VERSION 5.8 ;
BUSBITCHARS "[]" ;
DIVIDERCHAR "/" ;
UNITS
    DATABASE MICRONS 2000 ;
END UNITS

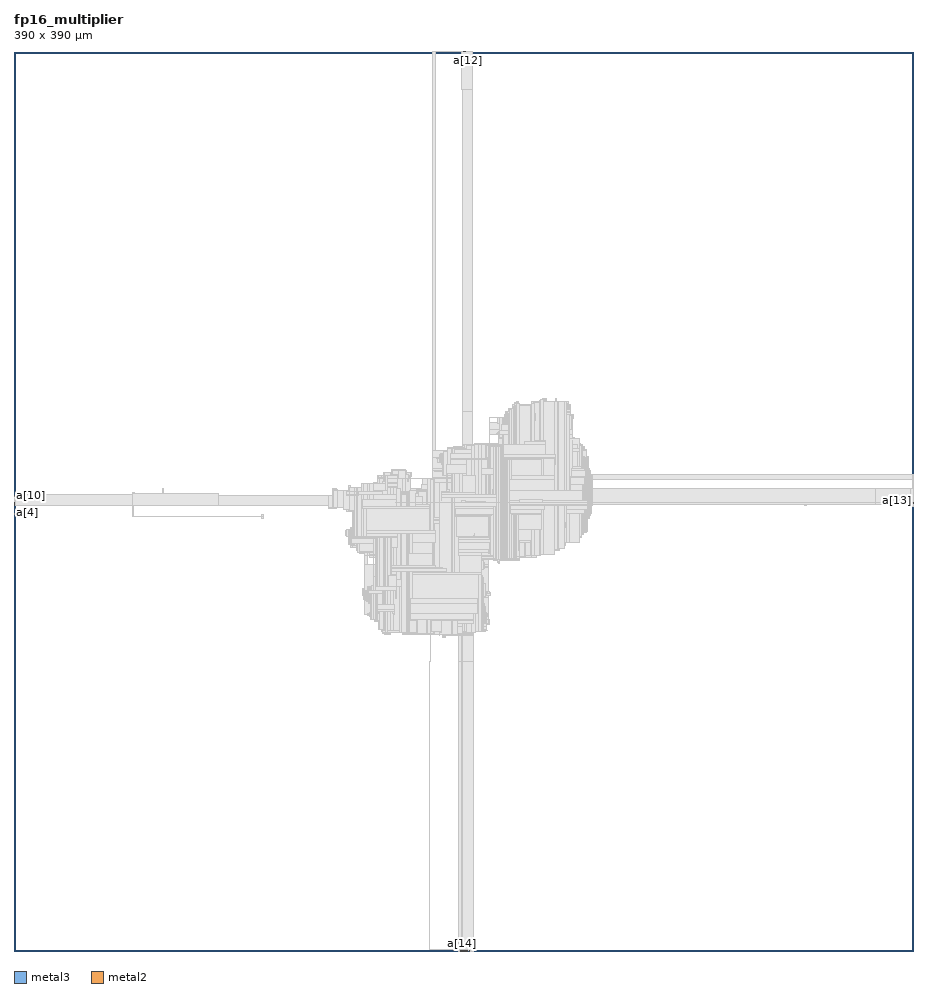
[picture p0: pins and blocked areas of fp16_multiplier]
MACRO fp16_multiplier
  FOREIGN fp16_multiplier 0 0 ;
  CLASS BLOCK ;
  SIZE 390 BY 390 ;
  PIN a[0]
    DIRECTION INPUT ;
    USE SIGNAL ;
    PORT
      LAYER metal3 ;
        RECT  0 194.915 0.07 194.985 ;
    END
  END a[0]
  PIN a[10]
    DIRECTION INPUT ;
    USE SIGNAL ;
    PORT
      LAYER metal3 ;
        RECT  0 197.155 0.07 197.225 ;
    END
  END a[10]
  PIN a[11]
    DIRECTION INPUT ;
    USE SIGNAL ;
    PORT
      LAYER metal3 ;
        RECT  0 196.035 0.07 196.105 ;
    END
  END a[11]
  PIN a[12]
    DIRECTION INPUT ;
    USE SIGNAL ;
    PORT
      LAYER metal2 ;
        RECT  196.9 389.93 196.97 390 ;
    END
  END a[12]
  PIN a[13]
    DIRECTION INPUT ;
    USE SIGNAL ;
    PORT
      LAYER metal3 ;
        RECT  389.93 195.195 390 195.265 ;
    END
  END a[13]
  PIN a[14]
    DIRECTION INPUT ;
    USE SIGNAL ;
    PORT
      LAYER metal2 ;
        RECT  194.24 0 194.31 0.07 ;
    END
  END a[14]
  PIN a[15]
    DIRECTION INPUT ;
    USE SIGNAL ;
    PORT
      LAYER metal3 ;
        RECT  0 193.795 0.07 193.865 ;
    END
  END a[15]
  PIN a[1]
    DIRECTION INPUT ;
    USE SIGNAL ;
    PORT
      LAYER metal3 ;
        RECT  389.93 196.875 390 196.945 ;
    END
  END a[1]
  PIN a[2]
    DIRECTION INPUT ;
    USE SIGNAL ;
    PORT
      LAYER metal3 ;
        RECT  389.93 197.715 390 197.785 ;
    END
  END a[2]
  PIN a[3]
    DIRECTION INPUT ;
    USE SIGNAL ;
    PORT
      LAYER metal2 ;
        RECT  196.14 0 196.21 0.07 ;
    END
  END a[3]
  PIN a[4]
    DIRECTION INPUT ;
    USE SIGNAL ;
    PORT
      LAYER metal3 ;
        RECT  0 193.235 0.07 193.305 ;
    END
  END a[4]
  PIN a[5]
    DIRECTION INPUT ;
    USE SIGNAL ;
    PORT
      LAYER metal2 ;
        RECT  195 0 195.07 0.07 ;
    END
  END a[5]
  PIN a[6]
    DIRECTION INPUT ;
    USE SIGNAL ;
    PORT
      LAYER metal2 ;
        RECT  194.62 0 194.69 0.07 ;
    END
  END a[6]
  PIN a[7]
    DIRECTION INPUT ;
    USE SIGNAL ;
    PORT
      LAYER metal3 ;
        RECT  389.93 193.515 390 193.585 ;
    END
  END a[7]
  PIN a[8]
    DIRECTION INPUT ;
    USE SIGNAL ;
    PORT
      LAYER metal2 ;
        RECT  195.76 389.93 195.83 390 ;
    END
  END a[8]
  PIN a[9]
    DIRECTION INPUT ;
    USE SIGNAL ;
    PORT
      LAYER metal2 ;
        RECT  193.86 389.93 193.93 390 ;
    END
  END a[9]
  PIN b[0]
    DIRECTION INPUT ;
    USE SIGNAL ;
    PORT
      LAYER metal2 ;
        RECT  194.62 389.93 194.69 390 ;
    END
  END b[0]
  PIN b[10]
    DIRECTION INPUT ;
    USE SIGNAL ;
    PORT
      LAYER metal2 ;
        RECT  193.86 0 193.93 0.07 ;
    END
  END b[10]
  PIN b[11]
    DIRECTION INPUT ;
    USE SIGNAL ;
    PORT
      LAYER metal3 ;
        RECT  389.93 192.675 390 192.745 ;
    END
  END b[11]
  PIN b[12]
    DIRECTION INPUT ;
    USE SIGNAL ;
    PORT
      LAYER metal3 ;
        RECT  389.93 195.475 390 195.545 ;
    END
  END b[12]
  PIN b[13]
    DIRECTION INPUT ;
    USE SIGNAL ;
    PORT
      LAYER metal2 ;
        RECT  195 389.93 195.07 390 ;
    END
  END b[13]
  PIN b[14]
    DIRECTION INPUT ;
    USE SIGNAL ;
    PORT
      LAYER metal3 ;
        RECT  389.93 196.035 390 196.105 ;
    END
  END b[14]
  PIN b[15]
    DIRECTION INPUT ;
    USE SIGNAL ;
    PORT
      LAYER metal3 ;
        RECT  389.93 194.355 390 194.425 ;
    END
  END b[15]
  PIN b[1]
    DIRECTION INPUT ;
    USE SIGNAL ;
    PORT
      LAYER metal3 ;
        RECT  0 194.355 0.07 194.425 ;
    END
  END b[1]
  PIN b[2]
    DIRECTION INPUT ;
    USE SIGNAL ;
    PORT
      LAYER metal2 ;
        RECT  195.38 389.93 195.45 390 ;
    END
  END b[2]
  PIN b[3]
    DIRECTION INPUT ;
    USE SIGNAL ;
    PORT
      LAYER metal2 ;
        RECT  195.38 0 195.45 0.07 ;
    END
  END b[3]
  PIN b[4]
    DIRECTION INPUT ;
    USE SIGNAL ;
    PORT
      LAYER metal3 ;
        RECT  0 194.075 0.07 194.145 ;
    END
  END b[4]
  PIN b[5]
    DIRECTION INPUT ;
    USE SIGNAL ;
    PORT
      LAYER metal2 ;
        RECT  196.52 389.93 196.59 390 ;
    END
  END b[5]
  PIN b[6]
    DIRECTION INPUT ;
    USE SIGNAL ;
    PORT
      LAYER metal3 ;
        RECT  389.93 195.755 390 195.825 ;
    END
  END b[6]
  PIN b[7]
    DIRECTION INPUT ;
    USE SIGNAL ;
    PORT
      LAYER metal2 ;
        RECT  197.28 0 197.35 0.07 ;
    END
  END b[7]
  PIN b[8]
    DIRECTION INPUT ;
    USE SIGNAL ;
    PORT
      LAYER metal3 ;
        RECT  0 196.595 0.07 196.665 ;
    END
  END b[8]
  PIN b[9]
    DIRECTION INPUT ;
    USE SIGNAL ;
    PORT
      LAYER metal3 ;
        RECT  389.93 196.595 390 196.665 ;
    END
  END b[9]
  PIN result[0]
    DIRECTION OUTPUT ;
    USE SIGNAL ;
    PORT
      LAYER metal2 ;
        RECT  194.24 389.93 194.31 390 ;
    END
  END result[0]
  PIN result[10]
    DIRECTION OUTPUT ;
    USE SIGNAL ;
    PORT
      LAYER metal3 ;
        RECT  389.93 194.075 390 194.145 ;
    END
  END result[10]
  PIN result[11]
    DIRECTION OUTPUT ;
    USE SIGNAL ;
    PORT
      LAYER metal3 ;
        RECT  0 193.515 0.07 193.585 ;
    END
  END result[11]
  PIN result[12]
    DIRECTION OUTPUT ;
    USE SIGNAL ;
    PORT
      LAYER metal3 ;
        RECT  389.93 193.795 390 193.865 ;
    END
  END result[12]
  PIN result[13]
    DIRECTION OUTPUT ;
    USE SIGNAL ;
    PORT
      LAYER metal2 ;
        RECT  193.48 0 193.55 0.07 ;
    END
  END result[13]
  PIN result[14]
    DIRECTION OUTPUT ;
    USE SIGNAL ;
    PORT
      LAYER metal2 ;
        RECT  195.76 0 195.83 0.07 ;
    END
  END result[14]
  PIN result[15]
    DIRECTION OUTPUT ;
    USE SIGNAL ;
    PORT
      LAYER metal3 ;
        RECT  0 194.635 0.07 194.705 ;
    END
  END result[15]
  PIN result[1]
    DIRECTION OUTPUT ;
    USE SIGNAL ;
    PORT
      LAYER metal3 ;
        RECT  0 195.195 0.07 195.265 ;
    END
  END result[1]
  PIN result[2]
    DIRECTION OUTPUT ;
    USE SIGNAL ;
    PORT
      LAYER metal3 ;
        RECT  389.93 196.315 390 196.385 ;
    END
  END result[2]
  PIN result[3]
    DIRECTION OUTPUT ;
    USE SIGNAL ;
    PORT
      LAYER metal3 ;
        RECT  389.93 194.915 390 194.985 ;
    END
  END result[3]
  PIN result[4]
    DIRECTION OUTPUT ;
    USE SIGNAL ;
    PORT
      LAYER metal3 ;
        RECT  0 195.755 0.07 195.825 ;
    END
  END result[4]
  PIN result[5]
    DIRECTION OUTPUT ;
    USE SIGNAL ;
    PORT
      LAYER metal3 ;
        RECT  0 195.475 0.07 195.545 ;
    END
  END result[5]
  PIN result[6]
    DIRECTION OUTPUT ;
    USE SIGNAL ;
    PORT
      LAYER metal2 ;
        RECT  196.52 0 196.59 0.07 ;
    END
  END result[6]
  PIN result[7]
    DIRECTION OUTPUT ;
    USE SIGNAL ;
    PORT
      LAYER metal3 ;
        RECT  0 196.315 0.07 196.385 ;
    END
  END result[7]
  PIN result[8]
    DIRECTION OUTPUT ;
    USE SIGNAL ;
    PORT
      LAYER metal2 ;
        RECT  193.48 389.93 193.55 390 ;
    END
  END result[8]
  PIN result[9]
    DIRECTION OUTPUT ;
    USE SIGNAL ;
    PORT
      LAYER metal3 ;
        RECT  389.93 194.635 390 194.705 ;
    END
  END result[9]
  OBS
    LAYER metal1 ;
     RECT  51.49 195.915 52.25 198.885 ;
     RECT  57 193.115 57.57 194.685 ;
     RECT  57.57 193.115 57.76 196.085 ;
     RECT  57.76 194.515 58.33 196.085 ;
     RECT  64.22 198.715 64.79 200.285 ;
     RECT  87.97 195.915 88.54 197.485 ;
     RECT  92.15 194.515 92.72 196.085 ;
     RECT  107.35 187.515 107.92 189.085 ;
     RECT  136.04 195.915 136.23 197.485 ;
     RECT  136.23 191.715 137.94 197.485 ;
     RECT  137.94 191.715 139.65 200.285 ;
     RECT  139.65 193.115 139.84 200.285 ;
     RECT  139.84 193.115 140.6 198.885 ;
     RECT  140.6 193.115 143.45 197.485 ;
     RECT  143.45 193.115 144.02 198.885 ;
     RECT  143.83 180.515 144.78 182.085 ;
     RECT  144.02 190.315 144.97 198.885 ;
     RECT  144.78 176.315 145.73 182.085 ;
     RECT  144.97 190.315 145.73 201.685 ;
     RECT  145.73 174.915 146.87 183.485 ;
     RECT  145.73 190.315 146.87 198.885 ;
     RECT  146.87 174.915 148.58 198.885 ;
     RECT  148.58 173.515 149.53 198.885 ;
     RECT  149.53 172.115 151.24 198.885 ;
     RECT  151.05 155.315 151.43 156.885 ;
     RECT  151.43 152.515 152.19 156.885 ;
     RECT  152.19 148.315 152.57 156.885 ;
     RECT  151.24 172.115 152.57 200.285 ;
     RECT  152.57 146.915 152.76 156.885 ;
     RECT  152.76 146.915 153.14 158.285 ;
     RECT  152.57 172.115 154.09 201.685 ;
     RECT  153.14 145.515 154.47 158.285 ;
     RECT  154.47 144.115 155.8 158.285 ;
     RECT  154.09 170.715 155.8 201.685 ;
     RECT  155.8 144.115 156.37 162.485 ;
     RECT  156.37 142.715 156.56 162.485 ;
     RECT  155.8 170.715 156.56 203.085 ;
     RECT  156.56 142.715 157.32 203.085 ;
     RECT  157.32 142.715 157.89 205.885 ;
     RECT  157.89 139.915 159.22 205.885 ;
     RECT  159.22 138.515 160.17 205.885 ;
     RECT  160.17 138.515 160.55 207.285 ;
     RECT  160.55 137.115 163.21 207.285 ;
     RECT  163.21 138.515 163.4 207.285 ;
     RECT  163.4 138.515 168.34 208.685 ;
     RECT  168.34 137.115 169.86 208.685 ;
     RECT  169.86 137.115 171.76 207.285 ;
     RECT  171.76 205.715 172.33 207.285 ;
     RECT  171.76 137.115 176.89 200.285 ;
     RECT  176.89 137.115 180.12 203.085 ;
     RECT  180.12 137.115 181.64 204.485 ;
     RECT  181.64 137.115 182.97 208.685 ;
     RECT  182.97 137.115 184.49 212.885 ;
     RECT  184.49 137.115 185.63 215.685 ;
     RECT  185.63 137.115 185.82 217.085 ;
     RECT  185.82 135.715 187.15 217.085 ;
     RECT  187.15 137.115 190.38 217.085 ;
     RECT  190.38 137.115 192.09 218.485 ;
     RECT  192.09 138.515 197.22 218.485 ;
     RECT  197.22 137.115 198.93 218.485 ;
     RECT  198.93 138.515 199.5 218.485 ;
     RECT  199.5 138.515 203.49 219.885 ;
     RECT  203.49 141.315 203.87 219.885 ;
     RECT  203.87 165.115 204.06 168.085 ;
     RECT  203.87 141.315 204.44 159.685 ;
     RECT  204.44 141.315 204.63 158.285 ;
     RECT  204.63 153.915 204.82 158.285 ;
     RECT  204.63 141.315 205.2 147.085 ;
     RECT  205.2 141.315 205.77 144.285 ;
     RECT  205.77 141.315 205.96 142.885 ;
     RECT  204.82 153.915 206.34 155.485 ;
     RECT  203.87 172.115 206.91 219.885 ;
     RECT  206.91 170.715 207.86 219.885 ;
     RECT  209.19 223.915 209.38 225.485 ;
     RECT  207.86 169.315 209.95 219.885 ;
     RECT  209.95 167.915 210.33 219.885 ;
     RECT  209.38 223.915 210.33 229.685 ;
     RECT  210.33 167.915 210.52 229.685 ;
     RECT  210.52 169.315 210.9 229.685 ;
     RECT  210.9 169.315 212.61 231.085 ;
     RECT  212.61 169.315 212.99 232.485 ;
     RECT  212.99 169.315 214.32 233.885 ;
     RECT  214.32 169.315 216.03 235.285 ;
     RECT  216.03 169.315 217.74 236.685 ;
     RECT  217.74 169.315 218.5 238.085 ;
     RECT  218.5 169.315 219.26 236.685 ;
     RECT  219.26 170.715 224.2 236.685 ;
     RECT  224.2 170.715 226.48 238.085 ;
     RECT  226.48 172.115 228.95 238.085 ;
     RECT  228.95 172.115 230.66 239.485 ;
     RECT  230.66 172.115 231.42 238.085 ;
     RECT  231.42 173.515 234.46 238.085 ;
     RECT  234.46 173.515 235.03 239.485 ;
     RECT  235.03 173.515 236.36 238.085 ;
     RECT  236.36 174.915 238.64 238.085 ;
     RECT  238.64 177.715 240.35 238.085 ;
     RECT  240.35 177.715 240.54 236.685 ;
     RECT  240.54 179.115 240.73 236.685 ;
     RECT  240.73 228.115 241.11 236.685 ;
     RECT  241.11 228.115 241.68 232.485 ;
     RECT  241.68 230.915 242.25 232.485 ;
     RECT  240.73 179.115 243.01 222.685 ;
     RECT  243.01 179.115 244.53 221.285 ;
     RECT  244.53 177.715 244.72 221.285 ;
     RECT  244.72 177.715 245.1 219.885 ;
     RECT  245.1 179.115 245.48 219.885 ;
     RECT  245.48 179.115 246.05 218.485 ;
     RECT  246.05 180.515 246.81 218.485 ;
     RECT  246.81 181.915 247.19 218.485 ;
     RECT  247.19 181.915 247.57 215.685 ;
     RECT  247.57 181.915 248.33 208.685 ;
     RECT  248.33 187.515 248.9 208.685 ;
     RECT  247.57 212.715 249.09 214.285 ;
     RECT  248.9 187.515 249.28 205.885 ;
     RECT  249.28 187.515 249.47 189.085 ;
     RECT  249.28 193.115 249.66 203.085 ;
     RECT  249.66 193.115 250.61 194.685 ;
     RECT  249.66 198.715 250.99 200.285 ;
     RECT  342.76 193.115 343.52 194.685 ;
    LAYER metal2 ;
     RECT  192.53 0 193.36 0.035 ;
     RECT  197.47 0 199.25 0.035 ;
     RECT  179.99 0.56 180.06 125.365 ;
     RECT  179.99 125.365 180.44 125.435 ;
     RECT  192.53 0.035 199.25 125.435 ;
     RECT  185.88 136.36 186.9 136.395 ;
     RECT  185.5 136.395 186.9 136.92 ;
     RECT  192.53 125.435 199.06 136.92 ;
     RECT  180.37 125.435 180.44 137.06 ;
     RECT  185.5 136.92 199.06 137.06 ;
     RECT  170.87 137.515 171.7 137.62 ;
     RECT  180.37 137.06 199.06 137.62 ;
     RECT  160.8 137.62 160.87 137.655 ;
     RECT  169.92 137.62 171.7 137.655 ;
     RECT  168.4 137.655 171.7 137.76 ;
     RECT  178.66 137.62 199.06 137.76 ;
     RECT  159.66 137.655 162.96 137.9 ;
     RECT  168.4 137.76 199.06 137.9 ;
     RECT  159.66 137.9 163.15 137.935 ;
     RECT  159.66 137.935 163.53 138.04 ;
     RECT  167.83 137.9 199.82 138.04 ;
     RECT  204.12 138.46 204.19 138.88 ;
     RECT  159.66 138.04 199.82 139.02 ;
     RECT  204.12 138.88 204.95 139.02 ;
     RECT  159.66 139.02 204.95 139.44 ;
     RECT  158.14 139.44 204.95 140.7 ;
     RECT  157.95 140.7 204.95 141.96 ;
     RECT  157.95 141.96 205.9 143.08 ;
     RECT  157.57 143.08 205.9 143.22 ;
     RECT  156.62 143.22 205.9 143.5 ;
     RECT  154.53 143.5 205.9 143.605 ;
     RECT  154.53 143.605 205.71 144.9 ;
     RECT  153.96 144.9 205.71 145.32 ;
     RECT  153.58 145.32 205.71 145.88 ;
     RECT  152.06 145.88 205.71 153.02 ;
     RECT  151.87 153.02 205.71 153.16 ;
     RECT  151.49 153.16 205.71 153.86 ;
     RECT  151.11 153.86 205.71 154.175 ;
     RECT  151.11 154.175 206.28 154.84 ;
     RECT  151.11 154.84 205.9 155.68 ;
     RECT  151.11 155.68 205.52 155.96 ;
     RECT  151.68 155.96 205.52 167.3 ;
     RECT  210.2 168.42 210.27 168.455 ;
     RECT  209.63 168.455 210.27 168.7 ;
     RECT  157 167.3 205.52 169.68 ;
     RECT  209.63 168.7 210.46 169.68 ;
     RECT  157 169.68 210.46 169.715 ;
     RECT  217.99 169.68 218.82 169.715 ;
     RECT  157 169.715 218.82 169.96 ;
     RECT  157 169.96 219.2 170.94 ;
     RECT  157 170.94 221.1 171.08 ;
     RECT  157 171.08 221.48 171.22 ;
     RECT  151.68 167.3 153.08 171.5 ;
     RECT  157 171.22 223.95 171.5 ;
     RECT  151.68 171.5 227.94 172.62 ;
     RECT  149.02 172.62 227.94 172.76 ;
     RECT  233.95 171.78 234.02 172.76 ;
     RECT  149.02 172.76 234.02 173.88 ;
     RECT  149.02 173.88 235.54 173.915 ;
     RECT  149.02 173.915 236.3 174.02 ;
     RECT  148.83 174.02 236.3 174.055 ;
     RECT  148.45 174.055 236.3 174.335 ;
     RECT  148.45 174.335 236.49 174.44 ;
     RECT  148.45 174.44 238.58 175.56 ;
     RECT  145.79 175.56 238.58 175.595 ;
     RECT  145.79 175.595 238.77 176.12 ;
     RECT  145.41 176.12 238.77 176.68 ;
     RECT  145.03 176.68 238.77 176.96 ;
     RECT  144.84 176.96 238.77 178.115 ;
     RECT  144.84 178.115 239.34 178.36 ;
     RECT  244.97 176.82 245.04 178.36 ;
     RECT  144.84 178.36 240.29 178.92 ;
     RECT  144.84 178.92 240.48 178.955 ;
     RECT  244.59 178.36 245.04 178.955 ;
     RECT  144.84 178.955 245.04 179.48 ;
     RECT  144.84 179.48 245.99 179.62 ;
     RECT  144.27 179.62 245.99 179.9 ;
     RECT  143.89 179.9 245.99 180.74 ;
     RECT  143.89 180.74 246.37 181.16 ;
     RECT  143.89 181.16 246.56 181.3 ;
     RECT  144.08 181.3 248.08 182.42 ;
     RECT  144.08 182.42 248.27 182.56 ;
     RECT  145.79 182.56 248.08 182.98 ;
     RECT  146.17 182.98 248.08 183.12 ;
     RECT  146.74 183.12 248.08 183.26 ;
     RECT  146.93 183.26 248.08 186.62 ;
     RECT  146.93 186.62 248.65 186.9 ;
     RECT  147.31 186.9 248.65 188.16 ;
     RECT  107.79 188.16 107.86 188.3 ;
     RECT  147.31 188.16 248.84 188.3 ;
     RECT  147.31 188.3 249.41 188.86 ;
     RECT  147.31 188.86 249.6 189.56 ;
     RECT  147.31 189.56 250.36 190.82 ;
     RECT  145.22 190.82 250.36 191.1 ;
     RECT  144.84 191.1 250.36 191.24 ;
     RECT  142.75 191.24 250.36 192.08 ;
     RECT  139.14 192.08 250.36 192.115 ;
     RECT  138.76 192.115 250.36 192.22 ;
     RECT  136.48 192.22 250.36 192.36 ;
     RECT  136.67 192.36 250.36 192.92 ;
     RECT  0.06 192.92 0.13 193.76 ;
     RECT  388.61 192.64 388.68 193.76 ;
     RECT  137.05 192.92 250.36 193.9 ;
     RECT  0.06 193.76 0.51 194.04 ;
     RECT  57.06 193.9 57.13 194.04 ;
     RECT  388.61 193.76 389.06 194.18 ;
     RECT  343.2 194.32 343.27 194.46 ;
     RECT  137.05 193.9 250.55 194.6 ;
     RECT  388.42 194.18 389.06 194.74 ;
     RECT  57.44 194.32 57.51 195.02 ;
     RECT  92.59 195.02 92.66 195.16 ;
     RECT  388.61 194.74 389.06 195.3 ;
     RECT  57.44 195.02 57.7 195.44 ;
     RECT  57.44 195.44 58.08 195.72 ;
     RECT  388.61 195.3 389.25 195.72 ;
     RECT  57.44 195.72 57.51 196.42 ;
     RECT  0.06 194.04 0.89 196.56 ;
     RECT  51.55 188.16 51.62 196.7 ;
     RECT  64.66 193.9 64.73 196.7 ;
     RECT  0.06 196.56 0.7 196.84 ;
     RECT  51.55 196.7 52.19 196.84 ;
     RECT  137.05 194.6 250.17 196.84 ;
     RECT  388.61 195.72 389.82 197.26 ;
     RECT  0.63 196.84 0.7 197.68 ;
     RECT  51.55 196.84 52 197.68 ;
     RECT  51.55 197.68 51.62 198.1 ;
     RECT  88.41 197.12 88.48 198.1 ;
     RECT  137.81 196.84 250.17 198.1 ;
     RECT  144.65 198.1 250.17 198.38 ;
     RECT  145.22 198.38 250.17 198.485 ;
     RECT  64.28 196.7 64.73 199.08 ;
     RECT  137.81 198.1 140.16 199.185 ;
     RECT  145.41 198.485 250.17 199.22 ;
     RECT  171.63 199.22 250.17 199.5 ;
     RECT  64.28 199.08 64.35 199.64 ;
     RECT  138.19 199.185 140.16 199.64 ;
     RECT  171.63 199.5 250.93 199.64 ;
     RECT  138.38 199.64 140.16 199.78 ;
     RECT  174.48 199.64 250.55 200.06 ;
     RECT  389.37 197.26 389.82 200.34 ;
     RECT  145.41 199.22 167.52 200.48 ;
     RECT  145.41 200.48 166.38 200.9 ;
     RECT  150.73 200.9 166.38 201.46 ;
     RECT  176.76 200.06 250.55 202.265 ;
     RECT  176.95 202.265 250.55 202.3 ;
     RECT  176.95 202.3 250.17 202.44 ;
     RECT  150.73 201.46 150.8 202.58 ;
     RECT  155.86 201.46 166.38 202.72 ;
     RECT  156.62 202.72 166.38 202.86 ;
     RECT  180.18 202.44 250.17 202.965 ;
     RECT  157.57 202.86 166.38 203 ;
     RECT  170.3 203.56 170.37 203.595 ;
     RECT  389.37 200.34 389.63 204.54 ;
     RECT  157.76 203 166.38 204.82 ;
     RECT  170.3 203.595 170.75 204.82 ;
     RECT  180.56 202.965 250.17 204.82 ;
     RECT  157.76 204.82 170.75 204.855 ;
     RECT  157.76 204.855 171.51 205.1 ;
     RECT  157.76 205.1 171.7 205.24 ;
     RECT  160.23 205.24 171.7 205.38 ;
     RECT  181.51 204.82 250.17 205.38 ;
     RECT  161.18 205.38 171.7 205.52 ;
     RECT  161.18 205.52 171.51 206.08 ;
     RECT  161.18 206.08 171.13 206.22 ;
     RECT  164.22 206.22 171.13 206.64 ;
     RECT  389.56 204.54 389.63 206.64 ;
     RECT  164.22 206.64 170.18 208.005 ;
     RECT  164.22 208.005 169.8 208.04 ;
     RECT  181.51 205.38 249.79 208.04 ;
     RECT  164.22 208.04 165.24 208.285 ;
     RECT  164.22 208.285 164.29 208.32 ;
     RECT  181.51 208.04 249.41 209.16 ;
     RECT  181.51 209.16 249.03 213.64 ;
     RECT  181.51 213.64 248.27 213.885 ;
     RECT  181.51 213.885 247.89 216.685 ;
     RECT  187.78 216.685 247.89 217.245 ;
     RECT  187.78 217.245 247.13 217.98 ;
     RECT  194.24 217.98 246.56 219.24 ;
     RECT  194.24 219.24 199.82 219.38 ;
     RECT  204.12 219.24 246.56 219.38 ;
     RECT  206.02 219.38 246.56 219.485 ;
     RECT  206.02 219.485 245.42 219.52 ;
     RECT  210.01 219.52 244.85 222.04 ;
     RECT  206.02 219.52 206.09 223.86 ;
     RECT  210.01 222.04 242.19 223.86 ;
     RECT  206.02 223.86 242.19 225.96 ;
     RECT  206.02 225.96 242 228.9 ;
     RECT  210.58 228.9 242 230.44 ;
     RECT  211.15 230.44 242 230.685 ;
     RECT  206.02 228.9 206.09 231.14 ;
     RECT  212.48 230.685 242 231.28 ;
     RECT  212.67 231.28 242 231.7 ;
     RECT  212.86 231.7 242 231.98 ;
     RECT  212.86 231.98 242.19 232.12 ;
     RECT  212.86 232.12 241.24 233.205 ;
     RECT  213.05 233.205 241.24 233.24 ;
     RECT  213.62 233.24 241.24 233.38 ;
     RECT  213.81 233.38 241.24 233.66 ;
     RECT  194.24 219.38 198.68 233.735 ;
     RECT  214.38 233.66 241.24 234.5 ;
     RECT  214.57 234.5 241.24 234.78 ;
     RECT  215.71 234.78 241.24 235.06 ;
     RECT  216.09 235.06 241.24 236.04 ;
     RECT  217.04 236.04 241.24 236.285 ;
     RECT  217.04 236.285 219.77 236.46 ;
     RECT  224.07 236.285 241.24 236.845 ;
     RECT  224.07 236.845 240.29 236.88 ;
     RECT  224.07 236.88 240.1 237.265 ;
     RECT  217.04 236.46 219.01 237.3 ;
     RECT  224.26 237.265 240.1 237.3 ;
     RECT  217.04 237.3 218.06 237.545 ;
     RECT  225.21 237.3 239.53 237.545 ;
     RECT  217.99 237.545 218.06 237.58 ;
     RECT  225.21 237.545 239.34 237.72 ;
     RECT  227.68 237.72 239.34 238.245 ;
     RECT  234.52 238.245 239.34 238.28 ;
     RECT  227.68 238.245 230.6 238.7 ;
     RECT  228.06 238.7 230.6 238.84 ;
     RECT  229.77 238.84 230.41 239.085 ;
     RECT  234.52 238.28 235.16 239.085 ;
     RECT  194.24 233.735 198.49 373.315 ;
     RECT  181.51 216.685 182.53 389.76 ;
     RECT  193.86 373.315 198.49 389.76 ;
     RECT  181.51 389.76 181.58 389.9 ;
     RECT  193.48 389.76 198.49 389.965 ;
     RECT  195.95 389.965 198.49 390 ;
    LAYER metal3 ;
     RECT  0.025 192.955 0.035 196.805 ;
     RECT  0.035 192.955 0.595 197.225 ;
     RECT  0.595 192.955 51.515 197.645 ;
     RECT  51.515 192.955 88.515 198.065 ;
     RECT  51.515 188.195 107.895 188.265 ;
     RECT  88.515 192.955 136.445 197.225 ;
     RECT  136.445 192.255 138.155 197.225 ;
     RECT  138.155 192.255 138.345 199.465 ;
     RECT  138.345 192.255 140.195 199.745 ;
     RECT  140.195 192.255 142.715 199.605 ;
     RECT  143.855 179.935 144.045 180.005 ;
     RECT  144.045 179.935 144.235 182.525 ;
     RECT  144.235 179.655 144.805 182.525 ;
     RECT  144.805 176.995 144.995 182.525 ;
     RECT  142.715 191.275 145.185 199.605 ;
     RECT  144.995 176.715 145.375 182.525 ;
     RECT  145.185 190.855 145.375 199.605 ;
     RECT  145.375 176.155 145.755 182.525 ;
     RECT  145.755 175.875 146.135 182.945 ;
     RECT  146.135 175.875 146.705 183.085 ;
     RECT  146.705 175.595 146.895 183.225 ;
     RECT  146.895 175.595 147.085 184.905 ;
     RECT  147.085 175.595 147.275 186.025 ;
     RECT  147.275 175.595 147.655 187.145 ;
     RECT  145.375 190.855 147.655 200.865 ;
     RECT  147.655 175.595 148.605 200.865 ;
     RECT  148.605 174.615 148.985 200.865 ;
     RECT  148.985 172.655 150.695 200.865 ;
     RECT  151.075 153.895 151.455 155.925 ;
     RECT  150.695 172.655 151.645 202.545 ;
     RECT  151.455 153.195 151.835 155.925 ;
     RECT  151.835 153.055 152.215 156.065 ;
     RECT  152.215 152.075 152.595 156.065 ;
     RECT  152.595 151.655 152.66 156.065 ;
     RECT  151.645 172.515 152.975 202.545 ;
     RECT  152.025 145.915 153.165 145.985 ;
     RECT  152.66 151.515 153.165 156.065 ;
     RECT  153.165 145.915 153.545 146.125 ;
     RECT  153.165 151.515 153.545 157.745 ;
     RECT  153.545 145.355 153.735 146.125 ;
     RECT  153.735 145.355 153.925 146.405 ;
     RECT  153.545 150.395 153.925 157.745 ;
     RECT  153.925 144.935 154.115 146.405 ;
     RECT  152.975 171.535 154.255 202.545 ;
     RECT  154.115 144.935 154.305 146.545 ;
     RECT  154.305 144.935 154.495 146.685 ;
     RECT  153.925 150.395 154.495 158.025 ;
     RECT  154.495 143.535 154.875 158.025 ;
     RECT  154.875 143.535 155.825 158.305 ;
     RECT  155.705 162.155 155.825 162.225 ;
     RECT  154.255 171.675 155.825 202.545 ;
     RECT  155.825 143.535 156.585 162.225 ;
     RECT  155.825 171.675 156.585 202.685 ;
     RECT  156.585 143.255 156.965 167.265 ;
     RECT  156.965 143.255 157.155 167.685 ;
     RECT  156.585 171.675 157.155 202.825 ;
     RECT  157.155 143.255 157.535 202.825 ;
     RECT  157.535 143.255 157.725 202.965 ;
     RECT  158.105 139.475 158.295 139.545 ;
     RECT  157.725 143.255 158.295 204.785 ;
     RECT  158.295 139.475 160.195 204.785 ;
     RECT  160.195 139.475 160.385 205.345 ;
     RECT  160.385 139.195 160.575 205.345 ;
     RECT  160.575 138.775 160.955 205.345 ;
     RECT  160.955 138.215 161.145 205.345 ;
     RECT  161.145 138.215 161.855 206.185 ;
     RECT  161.855 138.215 162.045 200.865 ;
     RECT  162.045 138.775 163.185 200.865 ;
     RECT  163.185 139.055 164.515 200.865 ;
     RECT  164.515 161.035 165.845 200.865 ;
     RECT  161.855 204.715 166.085 206.185 ;
     RECT  166.085 204.715 166.655 206.325 ;
     RECT  164.515 139.055 167.225 158.025 ;
     RECT  165.845 161.035 167.555 200.445 ;
     RECT  167.225 138.075 167.795 158.025 ;
     RECT  167.555 161.035 167.795 197.645 ;
     RECT  166.655 204.715 169.835 208.005 ;
     RECT  167.795 137.935 170.075 197.645 ;
     RECT  170.075 137.795 170.645 197.645 ;
     RECT  170.645 137.795 171.165 199.185 ;
     RECT  169.835 204.715 171.165 206.605 ;
     RECT  171.165 137.935 171.355 199.185 ;
     RECT  171.165 204.715 171.355 206.045 ;
     RECT  171.355 138.215 171.595 199.185 ;
     RECT  171.355 204.715 171.735 205.485 ;
     RECT  171.595 138.215 174.395 199.605 ;
     RECT  174.395 138.215 174.445 199.185 ;
     RECT  174.445 137.935 174.825 199.185 ;
     RECT  171.735 204.715 176.915 204.785 ;
     RECT  174.825 137.795 178.625 199.185 ;
     RECT  178.625 137.655 179.195 199.185 ;
     RECT  176.915 202.195 179.195 204.785 ;
     RECT  179.195 137.655 180.665 204.785 ;
     RECT  180.665 137.655 181.615 204.225 ;
     RECT  181.615 137.655 182.045 185.045 ;
     RECT  181.615 187.915 182.185 204.225 ;
     RECT  181.475 389.795 182.425 389.865 ;
     RECT  182.995 213.535 183.375 213.605 ;
     RECT  183.375 211.715 183.565 213.605 ;
     RECT  182.045 137.095 184.265 185.045 ;
     RECT  184.265 136.955 184.515 185.045 ;
     RECT  182.185 187.915 184.515 202.965 ;
     RECT  183.565 211.575 184.515 213.605 ;
     RECT  184.515 211.575 184.705 215.145 ;
     RECT  184.705 211.575 185.085 215.425 ;
     RECT  185.085 211.015 185.275 215.425 ;
     RECT  182.235 207.935 185.655 208.005 ;
     RECT  185.655 205.975 185.845 208.005 ;
     RECT  185.275 211.015 185.845 215.705 ;
     RECT  185.845 205.975 186.225 215.705 ;
     RECT  186.225 205.975 187.745 216.405 ;
     RECT  184.515 136.955 189.455 202.965 ;
     RECT  187.745 205.975 189.455 217.945 ;
     RECT  189.455 136.955 189.975 217.945 ;
     RECT  189.975 158.235 190.735 217.945 ;
     RECT  189.975 136.955 192.065 155.085 ;
     RECT  192.065 137.655 192.635 155.085 ;
     RECT  192.635 138.495 192.875 155.085 ;
     RECT  190.735 158.235 192.875 217.665 ;
     RECT  179.955 0.595 193.255 0.665 ;
     RECT  193.255 0.455 193.825 0.665 ;
     RECT  193.825 0.175 194.205 0.665 ;
     RECT  182.425 389.655 194.345 389.865 ;
     RECT  192.875 138.495 195.155 217.665 ;
     RECT  194.205 0.175 195.865 0.805 ;
     RECT  195.155 138.495 196.105 219.345 ;
     RECT  196.105 138.215 196.165 219.345 ;
     RECT  196.165 138.215 196.295 219.205 ;
     RECT  195.865 0.175 196.625 0.665 ;
     RECT  194.345 389.795 196.625 389.865 ;
     RECT  196.625 0.175 197.765 0.245 ;
     RECT  196.295 137.935 198.335 219.205 ;
     RECT  198.335 176.715 199.715 219.205 ;
     RECT  198.335 137.935 199.855 173.145 ;
     RECT  199.855 138.495 201.235 173.145 ;
     RECT  199.715 176.715 201.235 219.345 ;
     RECT  201.235 138.495 202.705 219.345 ;
     RECT  202.705 138.495 202.895 162.505 ;
     RECT  202.895 138.495 203.275 161.665 ;
     RECT  203.275 138.495 203.465 139.125 ;
     RECT  203.275 141.995 203.465 161.665 ;
     RECT  202.705 165.515 203.655 169.085 ;
     RECT  203.465 141.995 203.845 150.745 ;
     RECT  203.655 165.795 203.845 168.385 ;
     RECT  203.845 141.995 204.035 150.465 ;
     RECT  203.845 165.795 204.035 167.545 ;
     RECT  203.465 138.495 204.225 138.985 ;
     RECT  204.035 141.995 204.225 149.205 ;
     RECT  203.465 153.615 204.225 159.425 ;
     RECT  202.705 172.515 204.225 219.345 ;
     RECT  204.225 153.755 204.415 157.605 ;
     RECT  204.225 172.515 204.605 219.065 ;
     RECT  204.225 141.995 204.795 146.545 ;
     RECT  204.415 154.175 204.795 155.645 ;
     RECT  204.225 138.915 204.985 138.985 ;
     RECT  204.795 146.335 205.175 146.405 ;
     RECT  204.795 154.875 205.365 155.645 ;
     RECT  204.035 166.355 205.365 166.425 ;
     RECT  204.795 141.995 205.555 143.465 ;
     RECT  204.605 172.515 205.58 218.925 ;
     RECT  205.555 142.555 205.935 142.625 ;
     RECT  205.365 155.575 205.935 155.645 ;
     RECT  205.58 172.375 205.935 218.925 ;
     RECT  205.935 172.375 206.365 218.645 ;
     RECT  206.365 171.535 207.695 218.645 ;
     RECT  207.695 170.975 207.885 218.645 ;
     RECT  207.885 170.275 208.455 218.645 ;
     RECT  208.455 169.995 208.835 218.645 ;
     RECT  208.835 169.855 209.025 218.645 ;
     RECT  205.985 231.035 209.405 231.105 ;
     RECT  209.215 224.035 209.595 224.105 ;
     RECT  209.595 224.035 209.785 224.805 ;
     RECT  209.785 223.895 209.975 224.805 ;
     RECT  209.025 169.715 210.115 218.645 ;
     RECT  209.975 222.355 210.355 225.085 ;
     RECT  209.405 228.655 210.355 231.105 ;
     RECT  210.115 169.855 210.735 218.645 ;
     RECT  210.735 169.855 211.115 219.205 ;
     RECT  211.115 169.855 211.685 219.345 ;
     RECT  210.355 222.355 211.685 231.105 ;
     RECT  211.685 169.855 212.015 231.105 ;
     RECT  212.015 169.995 212.445 231.105 ;
     RECT  212.445 169.995 212.635 231.245 ;
     RECT  212.635 169.995 212.775 231.525 ;
     RECT  212.775 170.135 213.205 231.525 ;
     RECT  213.205 170.135 213.585 233.205 ;
     RECT  213.585 170.135 213.775 233.345 ;
     RECT  213.775 170.135 214.535 233.625 ;
     RECT  214.535 170.135 215.675 234.745 ;
     RECT  215.675 170.135 216.245 235.025 ;
     RECT  216.245 170.135 217.005 236.005 ;
     RECT  217.005 169.995 217.195 236.005 ;
     RECT  217.195 169.995 217.715 236.425 ;
     RECT  217.715 170.975 217.765 236.425 ;
     RECT  217.765 170.975 219.045 237.265 ;
     RECT  219.045 170.975 221.135 177.205 ;
     RECT  221.135 171.115 221.515 177.205 ;
     RECT  221.515 171.255 223.745 177.205 ;
     RECT  219.045 180.075 223.745 236.425 ;
     RECT  223.745 171.255 223.985 236.425 ;
     RECT  223.985 171.535 224.415 236.425 ;
     RECT  224.415 171.535 225.745 237.265 ;
     RECT  225.745 171.535 227.645 237.545 ;
     RECT  227.645 171.535 227.975 238.665 ;
     RECT  227.975 171.815 228.025 238.665 ;
     RECT  228.025 171.815 229.495 238.805 ;
     RECT  229.495 171.815 234.055 238.245 ;
     RECT  234.055 174.055 235.385 238.245 ;
     RECT  235.385 174.195 236.145 238.245 ;
     RECT  236.145 174.475 238.615 238.245 ;
     RECT  238.615 176.855 239.375 238.245 ;
     RECT  239.375 235.655 239.945 237.265 ;
     RECT  239.945 235.655 240.135 236.145 ;
     RECT  239.375 176.855 240.515 232.645 ;
     RECT  240.515 225.855 240.705 232.645 ;
     RECT  240.135 235.655 240.705 236.005 ;
     RECT  240.705 235.935 240.895 236.005 ;
     RECT  240.705 225.855 241.465 231.945 ;
     RECT  241.465 225.855 241.655 231.805 ;
     RECT  241.655 229.355 241.845 231.805 ;
     RECT  241.845 229.355 242.035 229.425 ;
     RECT  241.655 225.855 242.225 225.925 ;
     RECT  240.515 176.855 244.885 222.005 ;
     RECT  244.885 176.855 245.075 219.205 ;
     RECT  245.075 179.515 246.025 219.205 ;
     RECT  246.025 180.775 246.405 219.205 ;
     RECT  246.405 181.195 246.595 214.445 ;
     RECT  246.595 181.335 246.975 214.445 ;
     RECT  246.405 217.595 246.975 217.665 ;
     RECT  246.975 181.335 247.165 214.305 ;
     RECT  247.165 181.335 247.735 213.605 ;
     RECT  247.735 181.335 248.115 182.525 ;
     RECT  247.735 186.095 248.115 213.605 ;
     RECT  248.115 182.455 248.305 182.525 ;
     RECT  248.115 186.655 248.685 213.605 ;
     RECT  248.685 188.195 248.875 213.605 ;
     RECT  248.875 188.335 249.065 213.605 ;
     RECT  249.065 188.335 249.445 209.125 ;
     RECT  249.445 188.895 249.635 208.145 ;
     RECT  249.635 189.595 249.79 208.145 ;
     RECT  249.79 189.595 249.825 208.005 ;
     RECT  249.825 189.595 249.89 206.605 ;
     RECT  249.89 192.955 250.205 206.605 ;
     RECT  249.89 189.595 250.395 189.665 ;
     RECT  250.205 193.655 250.585 206.605 ;
     RECT  250.585 193.655 373.315 200.305 ;
     RECT  373.315 193.515 388.575 200.305 ;
     RECT  250.585 204.435 389.475 206.605 ;
     RECT  389.475 206.535 389.665 206.605 ;
     RECT  388.575 192.675 389.855 200.305 ;
     RECT  389.855 192.675 389.965 197.785 ;
     RECT  389.965 197.015 390 197.645 ;
    LAYER metal4 ;
     RECT  194.065 0.14 194.205 137.62 ;
     RECT  184.265 136.92 184.405 137.9 ;
     RECT  184.265 137.9 184.685 138.18 ;
     RECT  184.265 138.18 185.245 138.32 ;
     RECT  192.105 137.62 194.205 140.42 ;
     RECT  192.105 140.42 194.485 141.96 ;
     RECT  180.905 138.32 185.245 143.08 ;
     RECT  170.265 141.12 170.405 143.22 ;
     RECT  180.905 143.08 186.085 143.36 ;
     RECT  192.105 141.96 199.245 143.36 ;
     RECT  170.265 143.22 174.325 143.5 ;
     RECT  180.905 143.36 199.245 143.5 ;
     RECT  170.265 143.5 199.245 143.64 ;
     RECT  164.385 139.72 164.525 146.02 ;
     RECT  164.385 146.02 165.085 146.3 ;
     RECT  171.665 143.64 199.245 146.3 ;
     RECT  157.665 146.16 157.805 147.14 ;
     RECT  164.105 146.3 165.085 147.14 ;
     RECT  157.665 147.14 165.085 147.98 ;
     RECT  157.385 147.98 165.085 150.22 ;
     RECT  171.665 146.3 200.925 150.78 ;
     RECT  171.945 150.78 200.925 152.88 ;
     RECT  165.505 152.88 165.645 154.14 ;
     RECT  157.385 150.22 159.485 154.84 ;
     RECT  153.745 154.84 159.485 156.1 ;
     RECT  156.545 156.1 159.485 156.24 ;
     RECT  165.505 154.14 165.925 156.24 ;
     RECT  156.545 156.24 165.925 157.92 ;
     RECT  162.425 157.92 165.925 162.68 ;
     RECT  172.505 152.88 201.205 163.1 ;
     RECT  163.265 162.68 165.925 163.24 ;
     RECT  172.505 163.1 202.605 164.22 ;
     RECT  163.545 163.24 165.925 164.36 ;
     RECT  172.505 164.22 187.205 164.36 ;
     RECT  163.545 164.36 187.205 165.9 ;
     RECT  163.545 165.9 185.525 166.32 ;
     RECT  163.545 166.32 182.445 167.02 ;
     RECT  192.945 164.22 202.605 171.22 ;
     RECT  171.105 167.02 181.325 172.2 ;
     RECT  192.665 171.22 202.605 172.48 ;
     RECT  155.705 162.12 155.845 172.76 ;
     RECT  152.905 172.76 155.845 173.18 ;
     RECT  192.665 172.48 205.405 173.88 ;
     RECT  163.545 167.02 164.525 174.72 ;
     RECT  149.825 173.18 155.845 176.54 ;
     RECT  172.505 172.2 181.325 176.82 ;
     RECT  192.665 173.88 206.245 176.82 ;
     RECT  218.425 173.74 218.565 178.08 ;
     RECT  192.665 176.82 206.525 178.36 ;
     RECT  146.465 176.54 155.845 178.78 ;
     RECT  146.465 178.78 156.685 179.34 ;
     RECT  163.545 174.72 166.205 179.34 ;
     RECT  192.665 178.36 206.245 179.34 ;
     RECT  146.465 179.34 166.205 179.48 ;
     RECT  149.265 179.48 166.205 179.62 ;
     RECT  192.665 179.34 205.405 179.62 ;
     RECT  152.625 179.62 166.205 180.88 ;
     RECT  172.505 176.82 182.725 180.88 ;
     RECT  152.625 180.88 182.725 182.42 ;
     RECT  218.425 178.08 224.165 182.56 ;
     RECT  239.145 183.4 239.285 184.52 ;
     RECT  239.145 184.52 239.565 185.64 ;
     RECT  191.545 179.62 205.405 188.3 ;
     RECT  191.265 188.3 205.405 188.86 ;
     RECT  191.265 188.86 206.805 189 ;
     RECT  218.425 182.56 228.645 189.28 ;
     RECT  239.425 185.64 239.565 189.56 ;
     RECT  246.985 186.76 247.125 189.56 ;
     RECT  216.185 189.28 228.645 189.7 ;
     RECT  215.345 189.7 228.645 191.38 ;
     RECT  239.425 189.56 247.125 191.38 ;
     RECT  152.625 182.42 179.925 191.66 ;
     RECT  191.265 189 207.645 191.66 ;
     RECT  151.225 191.66 179.925 192.5 ;
     RECT  190.985 191.66 207.645 192.78 ;
     RECT  215.345 191.38 230.045 193.2 ;
     RECT  239.425 191.38 248.525 193.2 ;
     RECT  174.185 192.5 179.925 193.48 ;
     RECT  215.345 193.2 248.525 193.62 ;
     RECT  389.785 194.32 389.925 194.46 ;
     RECT  214.785 193.62 248.525 195.16 ;
     RECT  151.225 192.5 165.925 195.58 ;
     RECT  185.105 195.16 185.245 196.56 ;
     RECT  190.985 192.78 209.045 196.56 ;
     RECT  174.185 193.48 177.125 196.84 ;
     RECT  143.945 197.26 144.085 197.54 ;
     RECT  185.105 196.56 209.045 197.68 ;
     RECT  143.945 197.54 149.405 197.82 ;
     RECT  155.705 195.58 165.925 197.82 ;
     RECT  185.105 197.68 207.645 197.82 ;
     RECT  174.185 196.84 175.445 198.38 ;
     RECT  175.305 198.38 175.445 198.52 ;
     RECT  185.105 197.82 200.085 198.8 ;
     RECT  185.105 198.8 188.605 199.08 ;
     RECT  143.945 197.82 144.085 199.22 ;
     RECT  214.785 195.16 246.565 199.5 ;
     RECT  155.705 197.82 161.725 199.64 ;
     RECT  207.505 197.82 207.645 199.92 ;
     RECT  187.625 199.08 188.605 200.06 ;
     RECT  241.105 199.5 246.565 202.3 ;
     RECT  155.705 199.64 160.885 202.44 ;
     RECT  159.625 202.44 160.885 203.28 ;
     RECT  160.185 203.28 160.885 203.84 ;
     RECT  160.745 203.84 160.885 203.98 ;
     RECT  214.785 199.5 234.245 204.12 ;
     RECT  241.105 202.3 247.405 205.1 ;
     RECT  241.105 205.1 247.685 205.66 ;
     RECT  194.345 198.8 200.085 206.08 ;
     RECT  215.625 204.12 234.245 206.08 ;
     RECT  202.465 206.08 202.605 206.36 ;
     RECT  194.345 206.08 196.165 206.78 ;
     RECT  187.625 200.06 187.765 206.92 ;
     RECT  193.785 206.78 196.165 206.92 ;
     RECT  241.385 205.66 247.685 208.18 ;
     RECT  241.385 208.18 247.405 208.88 ;
     RECT  241.385 208.88 246.005 209.16 ;
     RECT  202.465 206.36 207.925 209.3 ;
     RECT  241.945 209.16 246.005 210.14 ;
     RECT  187.625 206.92 196.165 210.84 ;
     RECT  234.665 210.98 234.805 212.52 ;
     RECT  215.625 206.08 228.645 212.94 ;
     RECT  189.025 210.84 196.165 213.08 ;
     RECT  202.465 209.3 205.125 213.08 ;
     RECT  211.985 212.94 228.645 213.22 ;
     RECT  234.385 212.52 234.805 213.22 ;
     RECT  189.025 213.08 205.125 213.5 ;
     RECT  204.985 213.5 205.125 213.92 ;
     RECT  211.985 213.22 234.805 214.06 ;
     RECT  211.985 214.06 234.525 215.04 ;
     RECT  189.025 213.5 198.125 215.6 ;
     RECT  241.945 210.14 244.045 216.58 ;
     RECT  190.985 215.6 198.125 217.28 ;
     RECT  190.985 217.28 196.165 217.7 ;
     RECT  241.945 216.58 245.165 217.84 ;
     RECT  196.025 217.7 196.165 219.38 ;
     RECT  211.985 215.04 230.325 219.38 ;
     RECT  241.945 217.84 244.045 219.38 ;
     RECT  221.225 219.38 230.325 220.78 ;
     RECT  225.425 220.78 230.325 221.06 ;
     RECT  225.425 221.06 226.685 221.2 ;
     RECT  241.945 219.38 242.085 221.2 ;
     RECT  225.425 221.2 225.565 222.6 ;
     RECT  211.985 219.38 214.085 223.72 ;
     RECT  210.585 223.72 214.085 225.4 ;
     RECT  211.145 225.4 214.085 228.2 ;
     RECT  213.945 228.2 214.085 232.96 ;
     RECT  225.985 230.02 226.125 233.1 ;
    LAYER metal5 ;
     RECT  143.945 199.08 149.265 199.22 ;
     RECT  149.265 197.68 159.575 199.22 ;
     RECT  159.575 197.68 163.965 197.82 ;
     RECT  165.225 194.32 193.785 194.46 ;
     RECT  193.785 194.32 195.605 195.02 ;
     RECT  199.105 180.04 199.385 180.18 ;
     RECT  199.385 180.04 199.525 180.74 ;
     RECT  195.605 194.32 204.285 194.74 ;
     RECT  204.285 194.32 218.985 194.46 ;
     RECT  218.985 194.32 228.925 195.58 ;
     RECT  228.925 194.32 389.925 194.46 ;
  END
END fp16_multiplier
END LIBRARY
